VERSION 5.7 ;
  NOWIREEXTENSIONATPIN ON ;
  DIVIDERCHAR "/" ;
  BUSBITCHARS "[]" ;
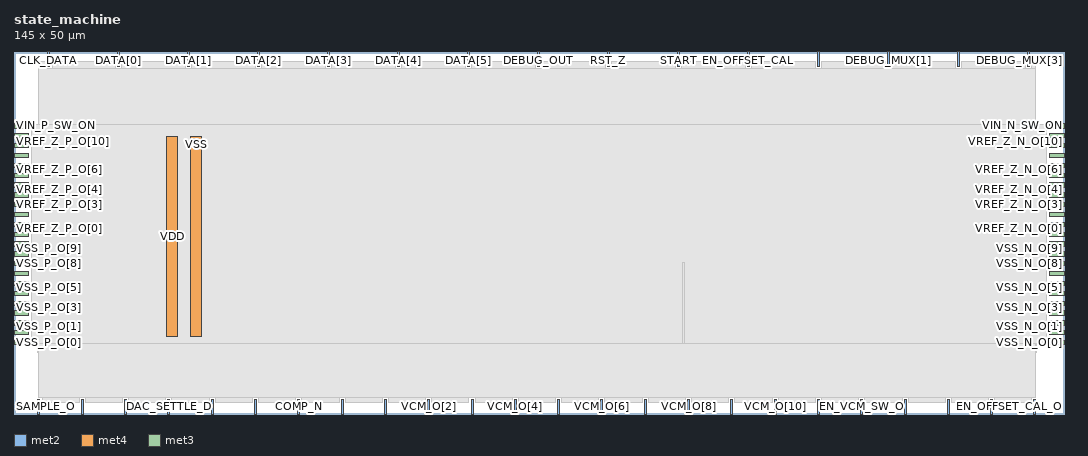
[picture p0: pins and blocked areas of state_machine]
MACRO state_machine
  CLASS BLOCK ;
  FOREIGN state_machine ;
  ORIGIN 0.000 0.000 ;
  SIZE 145.000 BY 50.000 ;
  PIN CLK_DATA
    DIRECTION OUTPUT ;
    USE SIGNAL ;
    ANTENNADIFFAREA 3.564000 ;
    PORT
      LAYER met2 ;
        RECT 4.690 48.000 4.970 50.000 ;
    END
  END CLK_DATA
  PIN COMP_N
    DIRECTION INPUT ;
    USE SIGNAL ;
    ANTENNAGATEAREA 0.373500 ;
    PORT
      LAYER met2 ;
        RECT 39.190 0.000 39.470 2.000 ;
    END
  END COMP_N
  PIN COMP_P
    DIRECTION INPUT ;
    USE SIGNAL ;
    ANTENNAGATEAREA 1.885500 ;
    PORT
      LAYER met2 ;
        RECT 33.210 0.000 33.490 2.000 ;
    END
  END COMP_P
  PIN DAC_SETTLE
    DIRECTION OUTPUT ;
    USE SIGNAL ;
    ANTENNAGATEAREA 0.126000 ;
    ANTENNADIFFAREA 0.429000 ;
    PORT
      LAYER met2 ;
        RECT 9.290 0.000 9.570 2.000 ;
    END
  END DAC_SETTLE
  PIN DAC_SETTLE_D
    DIRECTION INPUT ;
    USE SIGNAL ;
    ANTENNAGATEAREA 0.373500 ;
    PORT
      LAYER met2 ;
        RECT 21.250 0.000 21.530 2.000 ;
    END
  END DAC_SETTLE_D
  PIN DATA[0]
    DIRECTION OUTPUT ;
    USE SIGNAL ;
    ANTENNADIFFAREA 3.564000 ;
    PORT
      LAYER met2 ;
        RECT 14.350 48.000 14.630 50.000 ;
    END
  END DATA[0]
  PIN DATA[1]
    DIRECTION OUTPUT ;
    USE SIGNAL ;
    ANTENNADIFFAREA 3.564000 ;
    PORT
      LAYER met2 ;
        RECT 24.010 48.000 24.290 50.000 ;
    END
  END DATA[1]
  PIN DATA[2]
    DIRECTION OUTPUT ;
    USE SIGNAL ;
    ANTENNADIFFAREA 3.564000 ;
    PORT
      LAYER met2 ;
        RECT 33.670 48.000 33.950 50.000 ;
    END
  END DATA[2]
  PIN DATA[3]
    DIRECTION OUTPUT ;
    USE SIGNAL ;
    ANTENNADIFFAREA 3.564000 ;
    PORT
      LAYER met2 ;
        RECT 43.330 48.000 43.610 50.000 ;
    END
  END DATA[3]
  PIN DATA[4]
    DIRECTION OUTPUT ;
    USE SIGNAL ;
    ANTENNADIFFAREA 3.564000 ;
    PORT
      LAYER met2 ;
        RECT 52.990 48.000 53.270 50.000 ;
    END
  END DATA[4]
  PIN DATA[5]
    DIRECTION OUTPUT ;
    USE SIGNAL ;
    ANTENNADIFFAREA 3.564000 ;
    PORT
      LAYER met2 ;
        RECT 62.650 48.000 62.930 50.000 ;
    END
  END DATA[5]
  PIN DEBUG_MUX[0]
    DIRECTION INPUT ;
    USE SIGNAL ;
    ANTENNAGATEAREA 1.512000 ;
    PORT
      LAYER met2 ;
        RECT 110.950 48.000 111.230 50.000 ;
    END
  END DEBUG_MUX[0]
  PIN DEBUG_MUX[1]
    DIRECTION INPUT ;
    USE SIGNAL ;
    ANTENNAGATEAREA 1.008000 ;
    PORT
      LAYER met2 ;
        RECT 120.610 48.000 120.890 50.000 ;
    END
  END DEBUG_MUX[1]
  PIN DEBUG_MUX[2]
    DIRECTION INPUT ;
    USE SIGNAL ;
    ANTENNAGATEAREA 0.393000 ;
    PORT
      LAYER met2 ;
        RECT 130.270 48.000 130.550 50.000 ;
    END
  END DEBUG_MUX[2]
  PIN DEBUG_MUX[3]
    DIRECTION INPUT ;
    USE SIGNAL ;
    ANTENNAGATEAREA 0.303000 ;
    PORT
      LAYER met2 ;
        RECT 139.930 48.000 140.210 50.000 ;
    END
  END DEBUG_MUX[3]
  PIN DEBUG_OUT
    DIRECTION OUTPUT ;
    USE SIGNAL ;
    ANTENNADIFFAREA 3.564000 ;
    PORT
      LAYER met2 ;
        RECT 72.310 48.000 72.590 50.000 ;
    END
  END DEBUG_OUT
  PIN EN_COMP
    DIRECTION OUTPUT ;
    USE SIGNAL ;
    ANTENNAGATEAREA 0.126000 ;
    ANTENNADIFFAREA 0.891000 ;
    PORT
      LAYER met2 ;
        RECT 27.230 0.000 27.510 2.000 ;
    END
  END EN_COMP
  PIN EN_OFFSET_CAL
    DIRECTION INPUT ;
    USE SIGNAL ;
    ANTENNAGATEAREA 1.116000 ;
    PORT
      LAYER met2 ;
        RECT 101.290 48.000 101.570 50.000 ;
    END
  END EN_OFFSET_CAL
  PIN EN_OFFSET_CAL_O
    DIRECTION OUTPUT ;
    USE SIGNAL ;
    ANTENNADIFFAREA 0.445500 ;
    PORT
      LAYER met2 ;
        RECT 140.850 0.000 141.130 2.000 ;
    END
  END EN_OFFSET_CAL_O
  PIN EN_VCM_SW_O
    DIRECTION OUTPUT ;
    USE SIGNAL ;
    ANTENNAGATEAREA 0.126000 ;
    ANTENNADIFFAREA 0.891000 ;
    PORT
      LAYER met2 ;
        RECT 116.930 0.000 117.210 2.000 ;
    END
  END EN_VCM_SW_O
  PIN HI
    DIRECTION OUTPUT ;
    USE SIGNAL ;
    ANTENNAGATEAREA 0.378000 ;
    ANTENNADIFFAREA 0.891000 ;
    PORT
      LAYER met2 ;
        RECT 122.910 0.000 123.190 2.000 ;
    END
  END HI
  PIN LO
    DIRECTION OUTPUT ;
    USE SIGNAL ;
    ANTENNAGATEAREA 0.247500 ;
    ANTENNADIFFAREA 0.891000 ;
    PORT
      LAYER met2 ;
        RECT 128.890 0.000 129.170 2.000 ;
    END
  END LO
  PIN OFFSET_CAL_CYCLE
    DIRECTION OUTPUT ;
    USE SIGNAL ;
    ANTENNADIFFAREA 0.891000 ;
    PORT
      LAYER met2 ;
        RECT 134.870 0.000 135.150 2.000 ;
    END
  END OFFSET_CAL_CYCLE
  PIN RST_Z
    DIRECTION INPUT ;
    USE SIGNAL ;
    ANTENNAGATEAREA 0.990000 ;
    PORT
      LAYER met2 ;
        RECT 81.970 48.000 82.250 50.000 ;
    END
  END RST_Z
  PIN SAMPLE_D
    DIRECTION INPUT ;
    USE SIGNAL ;
    ANTENNAGATEAREA 0.499500 ;
    PORT
      LAYER met2 ;
        RECT 15.270 0.000 15.550 2.000 ;
    END
  END SAMPLE_D
  PIN SAMPLE_O
    DIRECTION OUTPUT ;
    USE SIGNAL ;
    ANTENNADIFFAREA 0.891000 ;
    PORT
      LAYER met2 ;
        RECT 3.310 0.000 3.590 2.000 ;
    END
  END SAMPLE_O
  PIN START
    DIRECTION INPUT ;
    USE SIGNAL ;
    ANTENNAGATEAREA 0.247500 ;
    PORT
      LAYER met2 ;
        RECT 91.630 48.000 91.910 50.000 ;
    END
  END START
  PIN VCM_DUMMY_O
    DIRECTION OUTPUT ;
    USE SIGNAL ;
    ANTENNADIFFAREA 0.891000 ;
    PORT
      LAYER met2 ;
        RECT 110.950 0.000 111.230 2.000 ;
    END
  END VCM_DUMMY_O
  PIN VCM_O[0]
    DIRECTION OUTPUT ;
    USE SIGNAL ;
    ANTENNAGATEAREA 0.247500 ;
    ANTENNADIFFAREA 0.891000 ;
    PORT
      LAYER met2 ;
        RECT 45.170 0.000 45.450 2.000 ;
    END
  END VCM_O[0]
  PIN VCM_O[10]
    DIRECTION OUTPUT ;
    USE SIGNAL ;
    ANTENNAGATEAREA 0.247500 ;
    ANTENNADIFFAREA 0.891000 ;
    PORT
      LAYER met2 ;
        RECT 104.970 0.000 105.250 2.000 ;
    END
  END VCM_O[10]
  PIN VCM_O[1]
    DIRECTION OUTPUT ;
    USE SIGNAL ;
    ANTENNAGATEAREA 0.247500 ;
    ANTENNADIFFAREA 0.891000 ;
    PORT
      LAYER met2 ;
        RECT 51.150 0.000 51.430 2.000 ;
    END
  END VCM_O[1]
  PIN VCM_O[2]
    DIRECTION OUTPUT ;
    USE SIGNAL ;
    ANTENNAGATEAREA 0.247500 ;
    ANTENNADIFFAREA 0.891000 ;
    PORT
      LAYER met2 ;
        RECT 57.130 0.000 57.410 2.000 ;
    END
  END VCM_O[2]
  PIN VCM_O[3]
    DIRECTION OUTPUT ;
    USE SIGNAL ;
    ANTENNAGATEAREA 0.247500 ;
    ANTENNADIFFAREA 0.891000 ;
    PORT
      LAYER met2 ;
        RECT 63.110 0.000 63.390 2.000 ;
    END
  END VCM_O[3]
  PIN VCM_O[4]
    DIRECTION OUTPUT ;
    USE SIGNAL ;
    ANTENNAGATEAREA 0.247500 ;
    ANTENNADIFFAREA 0.891000 ;
    PORT
      LAYER met2 ;
        RECT 69.090 0.000 69.370 2.000 ;
    END
  END VCM_O[4]
  PIN VCM_O[5]
    DIRECTION OUTPUT ;
    USE SIGNAL ;
    ANTENNAGATEAREA 0.247500 ;
    ANTENNADIFFAREA 0.891000 ;
    PORT
      LAYER met2 ;
        RECT 75.070 0.000 75.350 2.000 ;
    END
  END VCM_O[5]
  PIN VCM_O[6]
    DIRECTION OUTPUT ;
    USE SIGNAL ;
    ANTENNAGATEAREA 0.247500 ;
    ANTENNADIFFAREA 0.891000 ;
    PORT
      LAYER met2 ;
        RECT 81.050 0.000 81.330 2.000 ;
    END
  END VCM_O[6]
  PIN VCM_O[7]
    DIRECTION OUTPUT ;
    USE SIGNAL ;
    ANTENNAGATEAREA 0.247500 ;
    ANTENNADIFFAREA 0.891000 ;
    PORT
      LAYER met2 ;
        RECT 87.030 0.000 87.310 2.000 ;
    END
  END VCM_O[7]
  PIN VCM_O[8]
    DIRECTION OUTPUT ;
    USE SIGNAL ;
    ANTENNAGATEAREA 0.247500 ;
    ANTENNADIFFAREA 0.891000 ;
    PORT
      LAYER met2 ;
        RECT 93.010 0.000 93.290 2.000 ;
    END
  END VCM_O[8]
  PIN VCM_O[9]
    DIRECTION OUTPUT ;
    USE SIGNAL ;
    ANTENNAGATEAREA 0.247500 ;
    ANTENNADIFFAREA 0.891000 ;
    PORT
      LAYER met2 ;
        RECT 98.990 0.000 99.270 2.000 ;
    END
  END VCM_O[9]
  PIN VDD
    DIRECTION INOUT ;
    USE POWER ;
    PORT
      LAYER met4 ;
        RECT 21.040 10.640 22.640 38.320 ;
    END
  END VDD
  PIN VIN_N_SW_ON
    DIRECTION INPUT ;
    USE SIGNAL ;
    ANTENNAGATEAREA 0.247500 ;
    PORT
      LAYER met3 ;
        RECT 143.000 39.480 145.000 40.080 ;
    END
  END VIN_N_SW_ON
  PIN VIN_P_SW_ON
    DIRECTION INPUT ;
    USE SIGNAL ;
    ANTENNAGATEAREA 0.247500 ;
    ANTENNADIFFAREA 0.434700 ;
    PORT
      LAYER met3 ;
        RECT 0.000 39.480 2.000 40.080 ;
    END
  END VIN_P_SW_ON
  PIN VREF_Z_N_O[0]
    DIRECTION OUTPUT ;
    USE SIGNAL ;
    ANTENNADIFFAREA 0.891000 ;
    PORT
      LAYER met3 ;
        RECT 143.000 24.520 145.000 25.120 ;
    END
  END VREF_Z_N_O[0]
  PIN VREF_Z_N_O[10]
    DIRECTION OUTPUT ;
    USE SIGNAL ;
    ANTENNADIFFAREA 0.891000 ;
    PORT
      LAYER met3 ;
        RECT 143.000 38.120 145.000 38.720 ;
    END
  END VREF_Z_N_O[10]
  PIN VREF_Z_N_O[1]
    DIRECTION OUTPUT ;
    USE SIGNAL ;
    ANTENNADIFFAREA 0.891000 ;
    PORT
      LAYER met3 ;
        RECT 143.000 25.880 145.000 26.480 ;
    END
  END VREF_Z_N_O[1]
  PIN VREF_Z_N_O[2]
    DIRECTION OUTPUT ;
    USE SIGNAL ;
    ANTENNADIFFAREA 0.891000 ;
    PORT
      LAYER met3 ;
        RECT 143.000 27.240 145.000 27.840 ;
    END
  END VREF_Z_N_O[2]
  PIN VREF_Z_N_O[3]
    DIRECTION OUTPUT ;
    USE SIGNAL ;
    ANTENNADIFFAREA 0.891000 ;
    PORT
      LAYER met3 ;
        RECT 143.000 28.600 145.000 29.200 ;
    END
  END VREF_Z_N_O[3]
  PIN VREF_Z_N_O[4]
    DIRECTION OUTPUT ;
    USE SIGNAL ;
    ANTENNADIFFAREA 0.891000 ;
    PORT
      LAYER met3 ;
        RECT 143.000 29.960 145.000 30.560 ;
    END
  END VREF_Z_N_O[4]
  PIN VREF_Z_N_O[5]
    DIRECTION OUTPUT ;
    USE SIGNAL ;
    ANTENNADIFFAREA 0.891000 ;
    PORT
      LAYER met3 ;
        RECT 143.000 31.320 145.000 31.920 ;
    END
  END VREF_Z_N_O[5]
  PIN VREF_Z_N_O[6]
    DIRECTION OUTPUT ;
    USE SIGNAL ;
    ANTENNADIFFAREA 0.891000 ;
    PORT
      LAYER met3 ;
        RECT 143.000 32.680 145.000 33.280 ;
    END
  END VREF_Z_N_O[6]
  PIN VREF_Z_N_O[7]
    DIRECTION OUTPUT ;
    USE SIGNAL ;
    ANTENNADIFFAREA 0.891000 ;
    PORT
      LAYER met3 ;
        RECT 143.000 34.040 145.000 34.640 ;
    END
  END VREF_Z_N_O[7]
  PIN VREF_Z_N_O[8]
    DIRECTION OUTPUT ;
    USE SIGNAL ;
    ANTENNADIFFAREA 0.891000 ;
    PORT
      LAYER met3 ;
        RECT 143.000 35.400 145.000 36.000 ;
    END
  END VREF_Z_N_O[8]
  PIN VREF_Z_N_O[9]
    DIRECTION OUTPUT ;
    USE SIGNAL ;
    ANTENNADIFFAREA 0.891000 ;
    PORT
      LAYER met3 ;
        RECT 143.000 36.760 145.000 37.360 ;
    END
  END VREF_Z_N_O[9]
  PIN VREF_Z_P_O[0]
    DIRECTION OUTPUT ;
    USE SIGNAL ;
    ANTENNADIFFAREA 0.891000 ;
    PORT
      LAYER met3 ;
        RECT 0.000 24.520 2.000 25.120 ;
    END
  END VREF_Z_P_O[0]
  PIN VREF_Z_P_O[10]
    DIRECTION OUTPUT ;
    USE SIGNAL ;
    ANTENNADIFFAREA 0.891000 ;
    PORT
      LAYER met3 ;
        RECT 0.000 38.120 2.000 38.720 ;
    END
  END VREF_Z_P_O[10]
  PIN VREF_Z_P_O[1]
    DIRECTION OUTPUT ;
    USE SIGNAL ;
    ANTENNADIFFAREA 0.891000 ;
    PORT
      LAYER met3 ;
        RECT 0.000 25.880 2.000 26.480 ;
    END
  END VREF_Z_P_O[1]
  PIN VREF_Z_P_O[2]
    DIRECTION OUTPUT ;
    USE SIGNAL ;
    ANTENNADIFFAREA 0.891000 ;
    PORT
      LAYER met3 ;
        RECT 0.000 27.240 2.000 27.840 ;
    END
  END VREF_Z_P_O[2]
  PIN VREF_Z_P_O[3]
    DIRECTION OUTPUT ;
    USE SIGNAL ;
    ANTENNADIFFAREA 0.891000 ;
    PORT
      LAYER met3 ;
        RECT 0.000 28.600 2.000 29.200 ;
    END
  END VREF_Z_P_O[3]
  PIN VREF_Z_P_O[4]
    DIRECTION OUTPUT ;
    USE SIGNAL ;
    ANTENNADIFFAREA 0.891000 ;
    PORT
      LAYER met3 ;
        RECT 0.000 29.960 2.000 30.560 ;
    END
  END VREF_Z_P_O[4]
  PIN VREF_Z_P_O[5]
    DIRECTION OUTPUT ;
    USE SIGNAL ;
    ANTENNADIFFAREA 0.891000 ;
    PORT
      LAYER met3 ;
        RECT 0.000 31.320 2.000 31.920 ;
    END
  END VREF_Z_P_O[5]
  PIN VREF_Z_P_O[6]
    DIRECTION OUTPUT ;
    USE SIGNAL ;
    ANTENNADIFFAREA 0.891000 ;
    PORT
      LAYER met3 ;
        RECT 0.000 32.680 2.000 33.280 ;
    END
  END VREF_Z_P_O[6]
  PIN VREF_Z_P_O[7]
    DIRECTION OUTPUT ;
    USE SIGNAL ;
    ANTENNADIFFAREA 0.891000 ;
    PORT
      LAYER met3 ;
        RECT 0.000 34.040 2.000 34.640 ;
    END
  END VREF_Z_P_O[7]
  PIN VREF_Z_P_O[8]
    DIRECTION OUTPUT ;
    USE SIGNAL ;
    ANTENNADIFFAREA 0.891000 ;
    PORT
      LAYER met3 ;
        RECT 0.000 35.400 2.000 36.000 ;
    END
  END VREF_Z_P_O[8]
  PIN VREF_Z_P_O[9]
    DIRECTION OUTPUT ;
    USE SIGNAL ;
    ANTENNADIFFAREA 0.891000 ;
    PORT
      LAYER met3 ;
        RECT 0.000 36.760 2.000 37.360 ;
    END
  END VREF_Z_P_O[9]
  PIN VSS
    DIRECTION INOUT ;
    USE GROUND ;
    PORT
      LAYER met4 ;
        RECT 24.340 10.640 25.940 38.320 ;
    END
  END VSS
  PIN VSS_N_O[0]
    DIRECTION OUTPUT ;
    USE SIGNAL ;
    ANTENNADIFFAREA 0.891000 ;
    PORT
      LAYER met3 ;
        RECT 143.000 9.560 145.000 10.160 ;
    END
  END VSS_N_O[0]
  PIN VSS_N_O[10]
    DIRECTION OUTPUT ;
    USE SIGNAL ;
    ANTENNADIFFAREA 0.891000 ;
    PORT
      LAYER met3 ;
        RECT 143.000 23.160 145.000 23.760 ;
    END
  END VSS_N_O[10]
  PIN VSS_N_O[1]
    DIRECTION OUTPUT ;
    USE SIGNAL ;
    ANTENNADIFFAREA 0.891000 ;
    PORT
      LAYER met3 ;
        RECT 143.000 10.920 145.000 11.520 ;
    END
  END VSS_N_O[1]
  PIN VSS_N_O[2]
    DIRECTION OUTPUT ;
    USE SIGNAL ;
    ANTENNADIFFAREA 0.891000 ;
    PORT
      LAYER met3 ;
        RECT 143.000 12.280 145.000 12.880 ;
    END
  END VSS_N_O[2]
  PIN VSS_N_O[3]
    DIRECTION OUTPUT ;
    USE SIGNAL ;
    ANTENNADIFFAREA 0.891000 ;
    PORT
      LAYER met3 ;
        RECT 143.000 13.640 145.000 14.240 ;
    END
  END VSS_N_O[3]
  PIN VSS_N_O[4]
    DIRECTION OUTPUT ;
    USE SIGNAL ;
    ANTENNADIFFAREA 0.891000 ;
    PORT
      LAYER met3 ;
        RECT 143.000 15.000 145.000 15.600 ;
    END
  END VSS_N_O[4]
  PIN VSS_N_O[5]
    DIRECTION OUTPUT ;
    USE SIGNAL ;
    ANTENNADIFFAREA 0.891000 ;
    PORT
      LAYER met3 ;
        RECT 143.000 16.360 145.000 16.960 ;
    END
  END VSS_N_O[5]
  PIN VSS_N_O[6]
    DIRECTION OUTPUT ;
    USE SIGNAL ;
    ANTENNADIFFAREA 0.891000 ;
    PORT
      LAYER met3 ;
        RECT 143.000 17.720 145.000 18.320 ;
    END
  END VSS_N_O[6]
  PIN VSS_N_O[7]
    DIRECTION OUTPUT ;
    USE SIGNAL ;
    ANTENNADIFFAREA 0.891000 ;
    PORT
      LAYER met3 ;
        RECT 143.000 19.080 145.000 19.680 ;
    END
  END VSS_N_O[7]
  PIN VSS_N_O[8]
    DIRECTION OUTPUT ;
    USE SIGNAL ;
    ANTENNADIFFAREA 0.891000 ;
    PORT
      LAYER met3 ;
        RECT 143.000 20.440 145.000 21.040 ;
    END
  END VSS_N_O[8]
  PIN VSS_N_O[9]
    DIRECTION OUTPUT ;
    USE SIGNAL ;
    ANTENNADIFFAREA 0.891000 ;
    PORT
      LAYER met3 ;
        RECT 143.000 21.800 145.000 22.400 ;
    END
  END VSS_N_O[9]
  PIN VSS_P_O[0]
    DIRECTION OUTPUT ;
    USE SIGNAL ;
    ANTENNADIFFAREA 0.891000 ;
    PORT
      LAYER met3 ;
        RECT 0.000 9.560 2.000 10.160 ;
    END
  END VSS_P_O[0]
  PIN VSS_P_O[10]
    DIRECTION OUTPUT ;
    USE SIGNAL ;
    ANTENNADIFFAREA 0.891000 ;
    PORT
      LAYER met3 ;
        RECT 0.000 23.160 2.000 23.760 ;
    END
  END VSS_P_O[10]
  PIN VSS_P_O[1]
    DIRECTION OUTPUT ;
    USE SIGNAL ;
    ANTENNADIFFAREA 0.891000 ;
    PORT
      LAYER met3 ;
        RECT 0.000 10.920 2.000 11.520 ;
    END
  END VSS_P_O[1]
  PIN VSS_P_O[2]
    DIRECTION OUTPUT ;
    USE SIGNAL ;
    ANTENNADIFFAREA 0.891000 ;
    PORT
      LAYER met3 ;
        RECT 0.000 12.280 2.000 12.880 ;
    END
  END VSS_P_O[2]
  PIN VSS_P_O[3]
    DIRECTION OUTPUT ;
    USE SIGNAL ;
    ANTENNADIFFAREA 0.891000 ;
    PORT
      LAYER met3 ;
        RECT 0.000 13.640 2.000 14.240 ;
    END
  END VSS_P_O[3]
  PIN VSS_P_O[4]
    DIRECTION OUTPUT ;
    USE SIGNAL ;
    ANTENNADIFFAREA 0.891000 ;
    PORT
      LAYER met3 ;
        RECT 0.000 15.000 2.000 15.600 ;
    END
  END VSS_P_O[4]
  PIN VSS_P_O[5]
    DIRECTION OUTPUT ;
    USE SIGNAL ;
    ANTENNADIFFAREA 0.891000 ;
    PORT
      LAYER met3 ;
        RECT 0.000 16.360 2.000 16.960 ;
    END
  END VSS_P_O[5]
  PIN VSS_P_O[6]
    DIRECTION OUTPUT ;
    USE SIGNAL ;
    ANTENNADIFFAREA 0.891000 ;
    PORT
      LAYER met3 ;
        RECT 0.000 17.720 2.000 18.320 ;
    END
  END VSS_P_O[6]
  PIN VSS_P_O[7]
    DIRECTION OUTPUT ;
    USE SIGNAL ;
    ANTENNADIFFAREA 0.891000 ;
    PORT
      LAYER met3 ;
        RECT 0.000 19.080 2.000 19.680 ;
    END
  END VSS_P_O[7]
  PIN VSS_P_O[8]
    DIRECTION OUTPUT ;
    USE SIGNAL ;
    ANTENNADIFFAREA 0.891000 ;
    PORT
      LAYER met3 ;
        RECT 0.000 20.440 2.000 21.040 ;
    END
  END VSS_P_O[8]
  PIN VSS_P_O[9]
    DIRECTION OUTPUT ;
    USE SIGNAL ;
    ANTENNADIFFAREA 0.891000 ;
    PORT
      LAYER met3 ;
        RECT 0.000 21.800 2.000 22.400 ;
    END
  END VSS_P_O[9]
  OBS
      LAYER li1 ;
        RECT 5.520 10.795 139.380 38.165 ;
      LAYER met1 ;
        RECT 3.290 8.540 141.150 38.720 ;
      LAYER met2 ;
        RECT 3.320 47.720 4.410 48.690 ;
        RECT 5.250 47.720 14.070 48.690 ;
        RECT 14.910 47.720 23.730 48.690 ;
        RECT 24.570 47.720 33.390 48.690 ;
        RECT 34.230 47.720 43.050 48.690 ;
        RECT 43.890 47.720 52.710 48.690 ;
        RECT 53.550 47.720 62.370 48.690 ;
        RECT 63.210 47.720 72.030 48.690 ;
        RECT 72.870 47.720 81.690 48.690 ;
        RECT 82.530 47.720 91.350 48.690 ;
        RECT 92.190 47.720 101.010 48.690 ;
        RECT 101.850 47.720 110.670 48.690 ;
        RECT 111.510 47.720 120.330 48.690 ;
        RECT 121.170 47.720 129.990 48.690 ;
        RECT 130.830 47.720 139.650 48.690 ;
        RECT 140.490 47.720 141.120 48.690 ;
        RECT 3.320 2.280 141.120 47.720 ;
        RECT 3.870 1.630 9.010 2.280 ;
        RECT 9.850 1.630 14.990 2.280 ;
        RECT 15.830 1.630 20.970 2.280 ;
        RECT 21.810 1.630 26.950 2.280 ;
        RECT 27.790 1.630 32.930 2.280 ;
        RECT 33.770 1.630 38.910 2.280 ;
        RECT 39.750 1.630 44.890 2.280 ;
        RECT 45.730 1.630 50.870 2.280 ;
        RECT 51.710 1.630 56.850 2.280 ;
        RECT 57.690 1.630 62.830 2.280 ;
        RECT 63.670 1.630 68.810 2.280 ;
        RECT 69.650 1.630 74.790 2.280 ;
        RECT 75.630 1.630 80.770 2.280 ;
        RECT 81.610 1.630 86.750 2.280 ;
        RECT 87.590 1.630 92.730 2.280 ;
        RECT 93.570 1.630 98.710 2.280 ;
        RECT 99.550 1.630 104.690 2.280 ;
        RECT 105.530 1.630 110.670 2.280 ;
        RECT 111.510 1.630 116.650 2.280 ;
        RECT 117.490 1.630 122.630 2.280 ;
        RECT 123.470 1.630 128.610 2.280 ;
        RECT 129.450 1.630 134.590 2.280 ;
        RECT 135.430 1.630 140.570 2.280 ;
      LAYER met3 ;
        RECT 2.400 9.695 142.600 39.945 ;
      LAYER met4 ;
        RECT 92.295 9.695 92.625 20.905 ;
  END
END state_machine
END LIBRARY

